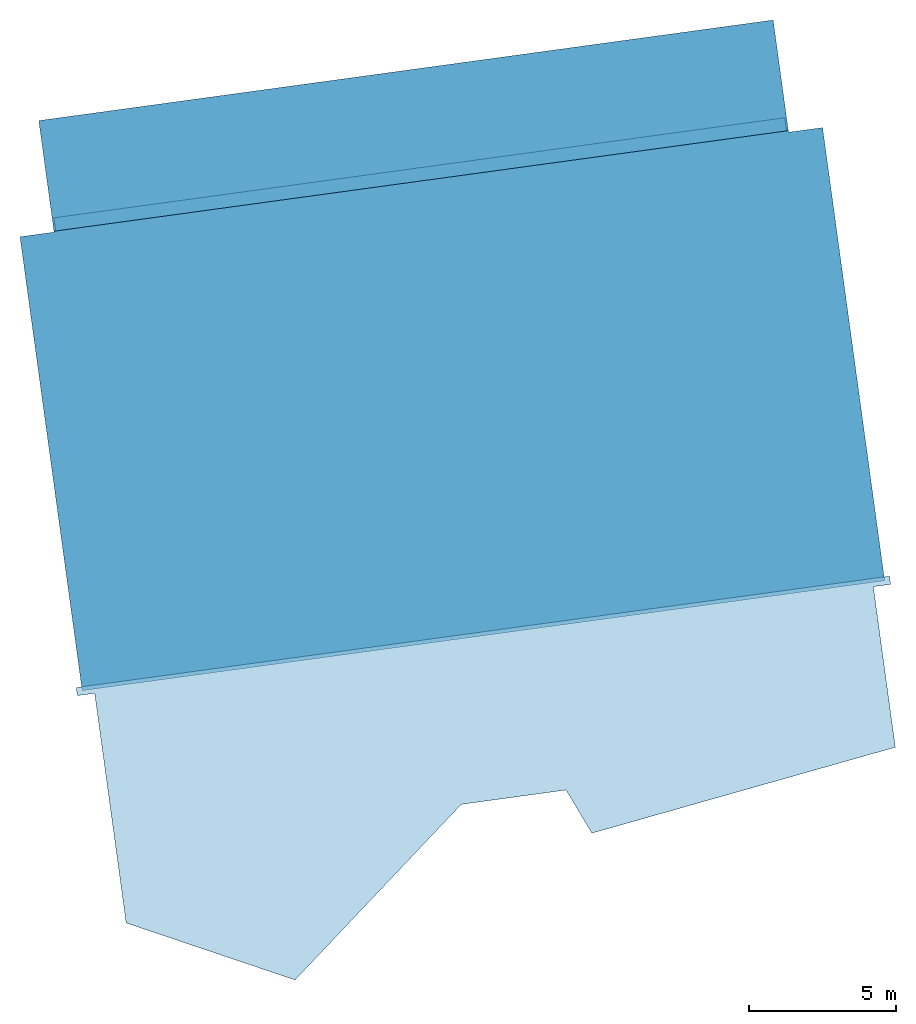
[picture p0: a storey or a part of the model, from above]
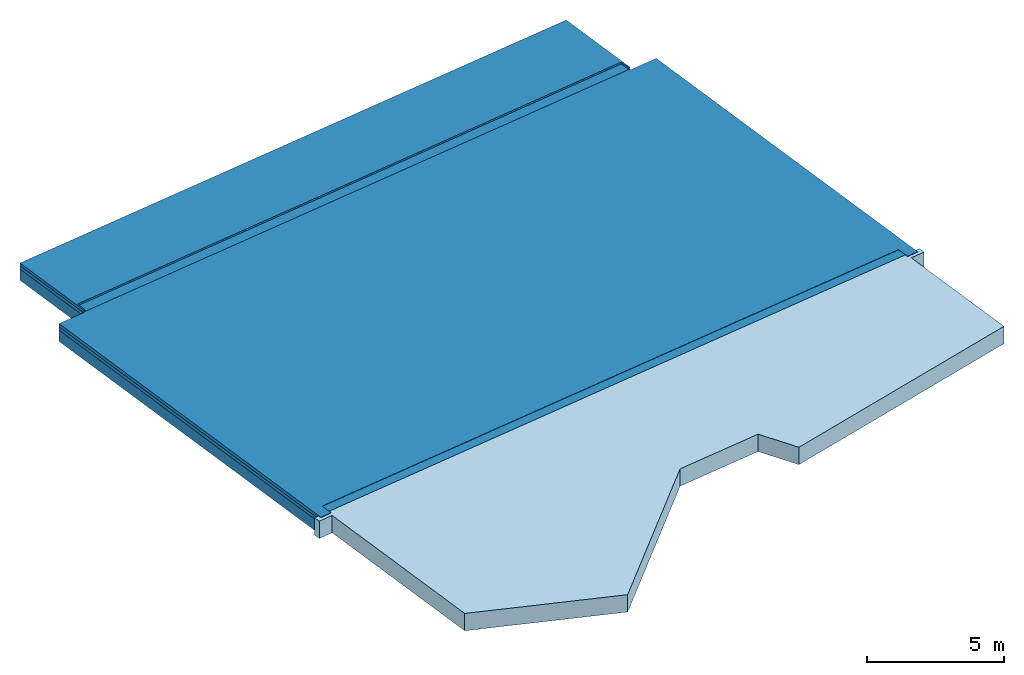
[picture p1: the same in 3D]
Properties of the parts of a building model (IFC2X3)

# File
Description: ViewDefinition [CoordinationView_V2.0], Option [Elements to export: Visible elements (on all stories)], Option [Partial Structure Display: Entire Model], Option [IFC Domain: All], Option [Structural Function: All Elements], Option [Convert Grid elements: On], Option [Convert IFC Annotations and Archicad 2D elements: Off], Option [Convert 2D symbols of Doors and Windows: Off], Option [Export geometries that Participates in Collision Detection only: Off], Option [Split complex elements: Off], Option [Material Preservation: Explode where necessary], Option [Elements in Solid Element Operations: Extruded/revolved], Option [Elements with junctions: Extruded/revolved], Option [IFC Model position: Survey Point and Project Origin], Option [Curtain Wall export mode: Single Element], Option [Railing export mode: Single Element], Option [Stair export mode: Single Element], Option [Properties To Export: All properties], Option [Space containment: Off], Option [Geometry to type objects: Off], Option [Element Properties: Off], Option [Building Material Properties: Off], Option [Element Parameters: Off], Option [Component Parameters: Off], Option [IFC Base Quantities: Off], Option [Door Window Parameters: On], Option [IFC Space boundaries: Off], Option [Archicad Zone Categories as IFC Space classification data: Off], Option [Element Classifications: On]
File name: G:\Projekte\FWS Neuwied\Sporthalle\AVA\03 Zimmer- und Holzbauarbeiten\Mit LV versenden\FWS Neuwied Sporthalle 2026-05-05.ifc
Time: 2026-05-05T07:56:59
Author: Architect
Organization: Building Designer Office
Written by: DDS_IFC v3.0
Made in: Graphisoft - Archicad - 29.0.0
Authorization: The authorising person

# IfcSite, Gelände
RefLatitude: 50, 22, 0, 0; RefLongitude: 7, 36, 0, 0; RefElevation: 0 m

# IfcBuildingStorey (5)
In: Gebäude
Name | Elevation (m)
Gelände | -3
ZG | 3
EG | 0
OG | 5.5
Dach | 9.9

# IfcBeam: Bauholz 120 x 15 (35)
In: EG
Classification: Balken / Unterzug (ARCHICAD Klassifizierung); Material: Bauholz
AC_Pset_RenovationAndPhasing - Renovation Status: Existing
Pset_BeamCommon - Reference: Bauholz 120 x 15

# IfcBeam: Bauholz 120 x 160 (46)
In: Dach
Classification: Balken / Unterzug (ARCHICAD Klassifizierung); Material: Bauholz
AC_Pset_RenovationAndPhasing - Renovation Status: Existing
Pset_BeamCommon - Reference: Bauholz 120 x 160

# IfcBeam: Bauholz 120 x 180 (46)
In: Dach
Classification: Balken / Unterzug (ARCHICAD Klassifizierung); Material: Bauholz
AC_Pset_RenovationAndPhasing - Renovation Status: Existing
Pset_BeamCommon - Reference: Bauholz 120 x 180

# IfcBeam: Bauholz 120 x 60 (105)
In: EG
Classification: Balken / Unterzug (ARCHICAD Klassifizierung); Material: Bauholz
AC_Pset_RenovationAndPhasing - Renovation Status: Existing
Pset_BeamCommon - Reference: Bauholz 120 x 60

# IfcBeam: Bauholz 140 x 240 (2)
In: ZG
Classification: Balken / Unterzug (ARCHICAD Klassifizierung); Material: Bauholz
AC_Pset_RenovationAndPhasing - Renovation Status: Existing
Pset_BeamCommon - Reference: Bauholz 140 x 240

# IfcBeam: Bauholz 180 x 120 (6)
In: EG
Classification: Balken / Unterzug (ARCHICAD Klassifizierung); Material: Bauholz
AC_Pset_RenovationAndPhasing - Renovation Status: Existing
Pset_BeamCommon - Reference: Bauholz 180 x 120

# IfcBeam: Bauholz 180 x 15 (18)
In: EG
Classification: Balken / Unterzug (ARCHICAD Klassifizierung); Material: Bauholz
AC_Pset_RenovationAndPhasing - Renovation Status: Existing
Pset_BeamCommon - Reference: Bauholz 180 x 15

# IfcBeam: Bauholz 180 x 60 (41)
In: EG
Classification: Balken / Unterzug (ARCHICAD Klassifizierung); Material: Bauholz
AC_Pset_RenovationAndPhasing - Renovation Status: Existing
Pset_BeamCommon - Reference: Bauholz 180 x 60

# IfcBeam: Bauholz 240 x 120 (23)
Classification: Balken / Unterzug (ARCHICAD Klassifizierung); Material: Bauholz
AC_Pset_RenovationAndPhasing - Renovation Status: Existing
Pset_BeamCommon - Reference: Bauholz 240 x 120
Name | In
21 x Unterzug-035 | ZG
2 x Unterzug-021 | OG

# IfcBeam: Bauholz 240 x 60 (14)
In: EG
Classification: Balken / Unterzug (ARCHICAD Klassifizierung); Material: Bauholz
AC_Pset_RenovationAndPhasing - Renovation Status: Existing
Pset_BeamCommon - Reference: Bauholz 240 x 60

# IfcBeam: Bauholz 240 x 80 (9)
In: EG
Classification: Balken / Unterzug (ARCHICAD Klassifizierung); Material: Bauholz
AC_Pset_RenovationAndPhasing - Renovation Status: Existing
Pset_BeamCommon - Reference: Bauholz 240 x 80

# IfcBeam: Holz, Bauholz 120 x 60 (50)
In: EG
Classification: Balken / Unterzug (ARCHICAD Klassifizierung); Material: Holz, Bauholz
AC_Pset_RenovationAndPhasing - Renovation Status: Existing
Pset_BeamCommon - Reference: Holz, Bauholz 120 x 60

# IfcBeam: Holz, Bauholz 180 x 60 (14)
In: EG
Classification: Balken / Unterzug (ARCHICAD Klassifizierung); Material: Holz, Bauholz
AC_Pset_RenovationAndPhasing - Renovation Status: Existing
Pset_BeamCommon - Reference: Holz, Bauholz 180 x 60
Name
2 x Unterzug-035
12 x Unterzug-021

# IfcBeam: Holz, Bauholz 240 x 120 (42)
Classification: Balken / Unterzug (ARCHICAD Klassifizierung); Material: Holz, Bauholz
Pset_BeamCommon - Reference: Holz, Bauholz 240 x 120
AC_Pset_RenovationAndPhasing - Renovation Status: Existing
Name | In
11 x Unterzug-021 | EG
7 x Unterzug-035 | ZG
10 x Unterzug-021 | ZG
14 x Unterzug-021 | OG

# IfcBeam: Holz, Bauholz 240 x 140 (6)
Classification: Balken / Unterzug (ARCHICAD Klassifizierung); Material: Holz, Bauholz
AC_Pset_RenovationAndPhasing - Renovation Status: Existing
Pset_BeamCommon - Reference: Holz, Bauholz 240 x 140
Name | In
2 x Unterzug-021 | EG
4 x Unterzug-021 | ZG

# IfcBeam: Holz, Bauholz 240 x 60 (18)
In: EG
Classification: Balken / Unterzug (ARCHICAD Klassifizierung); Material: Holz, Bauholz
Pset_BeamCommon - Reference: Holz, Bauholz 240 x 60
AC_Pset_RenovationAndPhasing - Renovation Status: Existing

# IfcBeam: Holz, Bauholz 240 x 80 (2)
In: EG
Classification: Balken / Unterzug (ARCHICAD Klassifizierung); Material: Holz, Bauholz
Pset_BeamCommon - Reference: Holz, Bauholz 240 x 80
AC_Pset_RenovationAndPhasing - Renovation Status: Existing

# IfcBeam: Holz, Bauholz-hart 100 x 200 (12)
In: ZG
Classification: Balken / Unterzug (ARCHICAD Klassifizierung); Material: Holz, Bauholz-hart
AC_Pset_RenovationAndPhasing - Renovation Status: Existing
Pset_BeamCommon - Reference: Holz, Bauholz-hart 100 x 200

# IfcBeam: Holz, Bauholz-hart 120 x 200 (8)
In: ZG
Classification: Balken / Unterzug (ARCHICAD Klassifizierung); Material: Holz, Bauholz-hart
AC_Pset_RenovationAndPhasing - Renovation Status: Existing
Pset_BeamCommon - Reference: Holz, Bauholz-hart 120 x 200

# IfcBeam: Holz, Bauholz-hart 120 x 60 (6)
In: EG
Classification: Balken / Unterzug (ARCHICAD Klassifizierung); Material: Holz, Bauholz-hart
AC_Pset_RenovationAndPhasing - Renovation Status: Existing
Pset_BeamCommon - Reference: Holz, Bauholz-hart 120 x 60

# IfcBeam: Holz, Bauholz-hart 180 x 60 (3)
In: EG
Classification: Balken / Unterzug (ARCHICAD Klassifizierung); Material: Holz, Bauholz-hart
Pset_BeamCommon - Reference: Holz, Bauholz-hart 180 x 60
AC_Pset_RenovationAndPhasing - Renovation Status: Existing
Name
Unterzug-035
2 x Unterzug-021

# IfcBeam: Holz, Bauholz-hart 240 x 120 (23)
Classification: Balken / Unterzug (ARCHICAD Klassifizierung); Material: Holz, Bauholz-hart
Pset_BeamCommon - Reference: Holz, Bauholz-hart 240 x 120
AC_Pset_RenovationAndPhasing - Renovation Status: Existing
Name | In
7 x Unterzug-021 | EG
8 x Unterzug-021 | ZG
8 x Unterzug-021 | OG

# IfcBeam: Holz, Bauholz-hart 240 x 60 (8)
In: EG
Classification: Balken / Unterzug (ARCHICAD Klassifizierung); Material: Holz, Bauholz-hart
AC_Pset_RenovationAndPhasing - Renovation Status: Existing
Pset_BeamCommon - Reference: Holz, Bauholz-hart 240 x 60

# IfcBeam: Holz, Bauholz-hart 240 x 80 (3)
In: EG
Classification: Balken / Unterzug (ARCHICAD Klassifizierung); Material: Holz, Bauholz-hart
AC_Pset_RenovationAndPhasing - Renovation Status: Existing
Pset_BeamCommon - Reference: Holz, Bauholz-hart 240 x 80

# IfcBeam: Holz, Bauholz-hart_UD 180 x 60 (2)
In: EG
Classification: Balken / Unterzug (ARCHICAD Klassifizierung); Material: Holz, Bauholz-hart_UD
AC_Pset_RenovationAndPhasing - Renovation Status: Existing
Pset_BeamCommon - Reference: Holz, Bauholz-hart_UD 180 x 60

# IfcBeam: Holz, Brettschichtholz 160 x 350 (7)
In: OG
Classification: Balken / Unterzug (ARCHICAD Klassifizierung); Material: Holz, Brettschichtholz
AC_Pset_RenovationAndPhasing - Renovation Status: Existing
Pset_BeamCommon - Reference: Holz, Brettschichtholz 160 x 350

# IfcBeam: Holz, Brettschichtholz 160 x 440 (7)
In: OG
Classification: Balken / Unterzug (ARCHICAD Klassifizierung); Material: Holz, Brettschichtholz
AC_Pset_RenovationAndPhasing - Renovation Status: Existing
Pset_BeamCommon - Reference: Holz, Brettschichtholz 160 x 440

# IfcBeam: Holz, Brettschichtholz 2000 x 160, Unterzug-031
In: OG
Classification: Balken / Unterzug (ARCHICAD Klassifizierung); Material: Holz, Brettschichtholz
AC_Pset_RenovationAndPhasing - Renovation Status: Existing
Pset_BeamCommon - Reference: Holz, Brettschichtholz 2000 x 160

# IfcBeam: Verschiedene Strukturen - 2 Segmente - 100 x 200 x 10107 (183+9924), Unterzug-034
In: ZG
Classification: Balken / Unterzug (ARCHICAD Klassifizierung)
AC_Pset_RenovationAndPhasing - Renovation Status: Existing
Pset_BeamCommon - Reference: Verschiedene Strukturen - 2 Segmente - 100 x 200 x 10107 (183+9924)

# IfcBeam: Verschiedene Strukturen - 2 Segmente - 100 x 200 x 10390 (183+10207), Unterzug-034
In: ZG
Classification: Balken / Unterzug (ARCHICAD Klassifizierung)
AC_Pset_RenovationAndPhasing - Renovation Status: Existing
Pset_BeamCommon - Reference: Verschiedene Strukturen - 2 Segmente - 100 x 200 x 10390 (183+10207)

# IfcBeam: Verschiedene Strukturen - 2 Segmente - 100 x 200 x 10497 (183+10315), Unterzug-034
In: ZG
Classification: Balken / Unterzug (ARCHICAD Klassifizierung)
Pset_BeamCommon - Reference: Verschiedene Strukturen - 2 Segmente - 100 x 200 x 10497 (183+10315)
AC_Pset_RenovationAndPhasing - Renovation Status: Existing

# IfcBeam: Verschiedene Strukturen - 2 Segmente - 100 x 200 x 10888 (183+10706), Unterzug-034
In: ZG
Classification: Balken / Unterzug (ARCHICAD Klassifizierung)
Pset_BeamCommon - Reference: Verschiedene Strukturen - 2 Segmente - 100 x 200 x 10888 (183+10706)
AC_Pset_RenovationAndPhasing - Renovation Status: Existing

# IfcBeam: Verschiedene Strukturen - 2 Segmente - 100 x 200 x 10897 (183+10714), Unterzug-034
In: ZG
Classification: Balken / Unterzug (ARCHICAD Klassifizierung)
AC_Pset_RenovationAndPhasing - Renovation Status: Existing
Pset_BeamCommon - Reference: Verschiedene Strukturen - 2 Segmente - 100 x 200 x 10897 (183+10714)

# IfcBeam: Verschiedene Strukturen - 2 Segmente - 100 x 200 x 11279 (183+11096), Unterzug-034
In: ZG
Classification: Balken / Unterzug (ARCHICAD Klassifizierung)
AC_Pset_RenovationAndPhasing - Renovation Status: Existing
Pset_BeamCommon - Reference: Verschiedene Strukturen - 2 Segmente - 100 x 200 x 11279 (183+11096)

# IfcBeam: Verschiedene Strukturen - 2 Segmente - 100 x 200 x 11416 (183+11234), Unterzug-034
In: ZG
Classification: Balken / Unterzug (ARCHICAD Klassifizierung)
Pset_BeamCommon - Reference: Verschiedene Strukturen - 2 Segmente - 100 x 200 x 11416 (183+11234)
AC_Pset_RenovationAndPhasing - Renovation Status: Existing

# IfcBeam: Verschiedene Strukturen - 2 Segmente - 100 x 200 x 1775 (1532+243) (2)
In: ZG
Classification: Balken / Unterzug (ARCHICAD Klassifizierung)
AC_Pset_RenovationAndPhasing - Renovation Status: Existing
Pset_BeamCommon - Reference: Verschiedene Strukturen - 2 Segmente - 100 x 200 x 1775 (1532+243)

# IfcBeam: Verschiedene Strukturen - 2 Segmente - 100 x 200 x 2865 (248+2617), Unterzug-034
In: ZG
Classification: Balken / Unterzug (ARCHICAD Klassifizierung)
AC_Pset_RenovationAndPhasing - Renovation Status: Existing
Pset_BeamCommon - Reference: Verschiedene Strukturen - 2 Segmente - 100 x 200 x 2865 (248+2617)

# IfcBeam: Verschiedene Strukturen - 2 Segmente - 100 x 200 x 3283 (248+3035), Unterzug-034
In: ZG
Classification: Balken / Unterzug (ARCHICAD Klassifizierung)
AC_Pset_RenovationAndPhasing - Renovation Status: Existing
Pset_BeamCommon - Reference: Verschiedene Strukturen - 2 Segmente - 100 x 200 x 3283 (248+3035)

# IfcBeam: Verschiedene Strukturen - 2 Segmente - 100 x 200 x 4243 (4076+167) (2)
In: ZG
Classification: Balken / Unterzug (ARCHICAD Klassifizierung)
AC_Pset_RenovationAndPhasing - Renovation Status: Existing
Pset_BeamCommon - Reference: Verschiedene Strukturen - 2 Segmente - 100 x 200 x 4243 (4076+167)

# IfcBeam: Verschiedene Strukturen - 2 Segmente - 100 x 200 x 4381 (4214+167) (37)
In: ZG
Classification: Balken / Unterzug (ARCHICAD Klassifizierung)
AC_Pset_RenovationAndPhasing - Renovation Status: Existing
Pset_BeamCommon - Reference: Verschiedene Strukturen - 2 Segmente - 100 x 200 x 4381 (4214+167)

# IfcBeam: Verschiedene Strukturen - 2 Segmente - 100 x 200 x 5298 (183+5116) (2)
In: ZG
Classification: Balken / Unterzug (ARCHICAD Klassifizierung)
AC_Pset_RenovationAndPhasing - Renovation Status: Existing
Pset_BeamCommon - Reference: Verschiedene Strukturen - 2 Segmente - 100 x 200 x 5298 (183+5116)

# IfcBeam: Verschiedene Strukturen - 2 Segmente - 100 x 200 x 5325 (183+5143), Unterzug-034
In: ZG
Classification: Balken / Unterzug (ARCHICAD Klassifizierung)
Pset_BeamCommon - Reference: Verschiedene Strukturen - 2 Segmente - 100 x 200 x 5325 (183+5143)
AC_Pset_RenovationAndPhasing - Renovation Status: Existing

# IfcBeam: Verschiedene Strukturen - 2 Segmente - 100 x 200 x 5412 (183+5229), Unterzug-034
In: ZG
Classification: Balken / Unterzug (ARCHICAD Klassifizierung)
AC_Pset_RenovationAndPhasing - Renovation Status: Existing
Pset_BeamCommon - Reference: Verschiedene Strukturen - 2 Segmente - 100 x 200 x 5412 (183+5229)

# IfcBeam: Verschiedene Strukturen - 2 Segmente - 100 x 200 x 5542 (183+5359), Unterzug-034
In: ZG
Classification: Balken / Unterzug (ARCHICAD Klassifizierung)
AC_Pset_RenovationAndPhasing - Renovation Status: Existing
Pset_BeamCommon - Reference: Verschiedene Strukturen - 2 Segmente - 100 x 200 x 5542 (183+5359)

# IfcBeam: Verschiedene Strukturen - 2 Segmente - 100 x 200 x 6435 (183+6253), Unterzug-034
In: ZG
Classification: Balken / Unterzug (ARCHICAD Klassifizierung)
Pset_BeamCommon - Reference: Verschiedene Strukturen - 2 Segmente - 100 x 200 x 6435 (183+6253)
AC_Pset_RenovationAndPhasing - Renovation Status: Existing

# IfcBeam: Verschiedene Strukturen - 2 Segmente - 100 x 200 x 6506 (183+6323), Unterzug-034
In: ZG
Classification: Balken / Unterzug (ARCHICAD Klassifizierung)
AC_Pset_RenovationAndPhasing - Renovation Status: Existing
Pset_BeamCommon - Reference: Verschiedene Strukturen - 2 Segmente - 100 x 200 x 6506 (183+6323)

# IfcBeam: Verschiedene Strukturen - 2 Segmente - 100 x 200 x 6565 (183+6383), Unterzug-034
In: ZG
Classification: Balken / Unterzug (ARCHICAD Klassifizierung)
Pset_BeamCommon - Reference: Verschiedene Strukturen - 2 Segmente - 100 x 200 x 6565 (183+6383)
AC_Pset_RenovationAndPhasing - Renovation Status: Existing

# IfcBeam: Verschiedene Strukturen - 2 Segmente - 100 x 200 x 6696 (183+6513), Unterzug-034
In: ZG
Classification: Balken / Unterzug (ARCHICAD Klassifizierung)
Pset_BeamCommon - Reference: Verschiedene Strukturen - 2 Segmente - 100 x 200 x 6696 (183+6513)
AC_Pset_RenovationAndPhasing - Renovation Status: Existing

# IfcBeam: Verschiedene Strukturen - 2 Segmente - 100 x 200 x 6826 (183+6643), Unterzug-034
In: ZG
Classification: Balken / Unterzug (ARCHICAD Klassifizierung)
Pset_BeamCommon - Reference: Verschiedene Strukturen - 2 Segmente - 100 x 200 x 6826 (183+6643)
AC_Pset_RenovationAndPhasing - Renovation Status: Existing

# IfcBeam: Verschiedene Strukturen - 2 Segmente - 100 x 200 x 6875 (183+6693), Unterzug-034
In: ZG
Classification: Balken / Unterzug (ARCHICAD Klassifizierung)
Pset_BeamCommon - Reference: Verschiedene Strukturen - 2 Segmente - 100 x 200 x 6875 (183+6693)
AC_Pset_RenovationAndPhasing - Renovation Status: Existing

# IfcBeam: Verschiedene Strukturen - 2 Segmente - 100 x 200 x 6969 (183+6786), Unterzug-034
In: ZG
Classification: Balken / Unterzug (ARCHICAD Klassifizierung)
AC_Pset_RenovationAndPhasing - Renovation Status: Existing
Pset_BeamCommon - Reference: Verschiedene Strukturen - 2 Segmente - 100 x 200 x 6969 (183+6786)

# IfcBeam: Verschiedene Strukturen - 2 Segmente - 100 x 200 x 7099 (183+6916), Unterzug-034
In: ZG
Classification: Balken / Unterzug (ARCHICAD Klassifizierung)
AC_Pset_RenovationAndPhasing - Renovation Status: Existing
Pset_BeamCommon - Reference: Verschiedene Strukturen - 2 Segmente - 100 x 200 x 7099 (183+6916)

# IfcBeam: Verschiedene Strukturen - 2 Segmente - 100 x 200 x 7229 (183+7046), Unterzug-034
In: ZG
Classification: Balken / Unterzug (ARCHICAD Klassifizierung)
AC_Pset_RenovationAndPhasing - Renovation Status: Existing
Pset_BeamCommon - Reference: Verschiedene Strukturen - 2 Segmente - 100 x 200 x 7229 (183+7046)

# IfcBeam: Verschiedene Strukturen - 2 Segmente - 100 x 200 x 7359 (183+7177), Unterzug-034
In: ZG
Classification: Balken / Unterzug (ARCHICAD Klassifizierung)
AC_Pset_RenovationAndPhasing - Renovation Status: Existing
Pset_BeamCommon - Reference: Verschiedene Strukturen - 2 Segmente - 100 x 200 x 7359 (183+7177)

# IfcBeam: Verschiedene Strukturen - 2 Segmente - 100 x 200 x 7489 (183+7307), Unterzug-034
In: ZG
Classification: Balken / Unterzug (ARCHICAD Klassifizierung)
AC_Pset_RenovationAndPhasing - Renovation Status: Existing
Pset_BeamCommon - Reference: Verschiedene Strukturen - 2 Segmente - 100 x 200 x 7489 (183+7307)

# IfcBeam: Verschiedene Strukturen - 2 Segmente - 100 x 200 x 7620 (183+7437), Unterzug-034
In: ZG
Classification: Balken / Unterzug (ARCHICAD Klassifizierung)
AC_Pset_RenovationAndPhasing - Renovation Status: Existing
Pset_BeamCommon - Reference: Verschiedene Strukturen - 2 Segmente - 100 x 200 x 7620 (183+7437)

# IfcBeam: Verschiedene Strukturen - 2 Segmente - 100 x 200 x 7750 (183+7567), Unterzug-034
In: ZG
Classification: Balken / Unterzug (ARCHICAD Klassifizierung)
AC_Pset_RenovationAndPhasing - Renovation Status: Existing
Pset_BeamCommon - Reference: Verschiedene Strukturen - 2 Segmente - 100 x 200 x 7750 (183+7567)

# IfcBeam: Verschiedene Strukturen - 2 Segmente - 100 x 200 x 8392 (183+8209), Unterzug-034
In: ZG
Classification: Balken / Unterzug (ARCHICAD Klassifizierung)
AC_Pset_RenovationAndPhasing - Renovation Status: Existing
Pset_BeamCommon - Reference: Verschiedene Strukturen - 2 Segmente - 100 x 200 x 8392 (183+8209)

# IfcBeam: Verschiedene Strukturen - 2 Segmente - 100 x 200 x 8869 (183+8686), Unterzug-034
In: ZG
Classification: Balken / Unterzug (ARCHICAD Klassifizierung)
AC_Pset_RenovationAndPhasing - Renovation Status: Existing
Pset_BeamCommon - Reference: Verschiedene Strukturen - 2 Segmente - 100 x 200 x 8869 (183+8686)

# IfcBeam: Verschiedene Strukturen - 2 Segmente - 100 x 200 x 9325 (183+9143), Unterzug-034
In: ZG
Classification: Balken / Unterzug (ARCHICAD Klassifizierung)
AC_Pset_RenovationAndPhasing - Renovation Status: Existing
Pset_BeamCommon - Reference: Verschiedene Strukturen - 2 Segmente - 100 x 200 x 9325 (183+9143)

# IfcBeam: Verschiedene Strukturen - 2 Segmente - 100 x 200 x 9376 (183+9193), Unterzug-034
In: ZG
Classification: Balken / Unterzug (ARCHICAD Klassifizierung)
AC_Pset_RenovationAndPhasing - Renovation Status: Existing
Pset_BeamCommon - Reference: Verschiedene Strukturen - 2 Segmente - 100 x 200 x 9376 (183+9193)

# IfcBeam: Verschiedene Strukturen - 2 Segmente - 100 x 200 x 9716 (183+9533), Unterzug-034
In: ZG
Classification: Balken / Unterzug (ARCHICAD Klassifizierung)
AC_Pset_RenovationAndPhasing - Renovation Status: Existing
Pset_BeamCommon - Reference: Verschiedene Strukturen - 2 Segmente - 100 x 200 x 9716 (183+9533)

# IfcBeam: Verschiedene Strukturen - 2 Segmente - 100 x 200 x 9883 (183+9700), Unterzug-034
In: ZG
Classification: Balken / Unterzug (ARCHICAD Klassifizierung)
Pset_BeamCommon - Reference: Verschiedene Strukturen - 2 Segmente - 100 x 200 x 9883 (183+9700)
AC_Pset_RenovationAndPhasing - Renovation Status: Existing

# IfcBeam: Verschiedene Strukturen - 2 Segmente - 120 x 200 x 11670 (183+11487), Unterzug-034
In: ZG
Classification: Balken / Unterzug (ARCHICAD Klassifizierung)
Pset_BeamCommon - Reference: Verschiedene Strukturen - 2 Segmente - 120 x 200 x 11670 (183+11487)
AC_Pset_RenovationAndPhasing - Renovation Status: Existing

# IfcBeam: Verschiedene Strukturen - 2 Segmente - 120 x 200 x 11923 (183+11741), Unterzug-034
In: ZG
Classification: Balken / Unterzug (ARCHICAD Klassifizierung)
AC_Pset_RenovationAndPhasing - Renovation Status: Existing
Pset_BeamCommon - Reference: Verschiedene Strukturen - 2 Segmente - 120 x 200 x 11923 (183+11741)

# IfcBeam: Verschiedene Strukturen - 2 Segmente - 120 x 200 x 7880 (183+7697), Unterzug-034
In: ZG
Classification: Balken / Unterzug (ARCHICAD Klassifizierung)
AC_Pset_RenovationAndPhasing - Renovation Status: Existing
Pset_BeamCommon - Reference: Verschiedene Strukturen - 2 Segmente - 120 x 200 x 7880 (183+7697)

# IfcBeam: Verschiedene Strukturen - 2 Segmente - 120 x 200 x 8252 (183+8070) (2)
In: ZG
Classification: Balken / Unterzug (ARCHICAD Klassifizierung)
Pset_BeamCommon - Reference: Verschiedene Strukturen - 2 Segmente - 120 x 200 x 8252 (183+8070)
AC_Pset_RenovationAndPhasing - Renovation Status: Existing

# IfcBeam: Verschiedene Strukturen - 2 Segmente - 120 x 200 x 8270 (183+8088), Unterzug-034
In: ZG
Classification: Balken / Unterzug (ARCHICAD Klassifizierung)
AC_Pset_RenovationAndPhasing - Renovation Status: Existing
Pset_BeamCommon - Reference: Verschiedene Strukturen - 2 Segmente - 120 x 200 x 8270 (183+8088)

# IfcBeam: Verschiedene Strukturen - 2 Segmente - 120 x 200 x 8379 (183+8197), Unterzug-034
In: ZG
Classification: Balken / Unterzug (ARCHICAD Klassifizierung)
Pset_BeamCommon - Reference: Verschiedene Strukturen - 2 Segmente - 120 x 200 x 8379 (183+8197)
AC_Pset_RenovationAndPhasing - Renovation Status: Existing

# IfcBeam: Verschiedene Strukturen - 2 Segmente - 180 x 200 x 8379 (183+8197) (2)
In: ZG
Classification: Balken / Unterzug (ARCHICAD Klassifizierung)
AC_Pset_RenovationAndPhasing - Renovation Status: Existing
Pset_BeamCommon - Reference: Verschiedene Strukturen - 2 Segmente - 180 x 200 x 8379 (183+8197)

# IfcBeam: Verschiedene Strukturen - 2 Segmente - 80 x 200 x 1055 (240+815), Unterzug-034
In: ZG
Classification: Balken / Unterzug (ARCHICAD Klassifizierung)
AC_Pset_RenovationAndPhasing - Renovation Status: Existing
Pset_BeamCommon - Reference: Verschiedene Strukturen - 2 Segmente - 80 x 200 x 1055 (240+815)

# IfcBeam: Verschiedene Strukturen - 2 Segmente - 80 x 200 x 1131 (183+949), Unterzug-034
In: ZG
Classification: Balken / Unterzug (ARCHICAD Klassifizierung)
AC_Pset_RenovationAndPhasing - Renovation Status: Existing
Pset_BeamCommon - Reference: Verschiedene Strukturen - 2 Segmente - 80 x 200 x 1131 (183+949)

# IfcBeam: Verschiedene Strukturen - 2 Segmente - 80 x 200 x 1207 (183+1024), Unterzug-034
In: ZG
Classification: Balken / Unterzug (ARCHICAD Klassifizierung)
AC_Pset_RenovationAndPhasing - Renovation Status: Existing
Pset_BeamCommon - Reference: Verschiedene Strukturen - 2 Segmente - 80 x 200 x 1207 (183+1024)

# IfcBeam: Verschiedene Strukturen - 2 Segmente - 80 x 200 x 1312 (1072+240) (2)
In: ZG
Classification: Balken / Unterzug (ARCHICAD Klassifizierung)
AC_Pset_RenovationAndPhasing - Renovation Status: Existing
Pset_BeamCommon - Reference: Verschiedene Strukturen - 2 Segmente - 80 x 200 x 1312 (1072+240)

# IfcBeam: Verschiedene Strukturen - 2 Segmente - 80 x 200 x 1347 (182+1165), Unterzug-034
In: ZG
Classification: Balken / Unterzug (ARCHICAD Klassifizierung)
AC_Pset_RenovationAndPhasing - Renovation Status: Existing
Pset_BeamCommon - Reference: Verschiedene Strukturen - 2 Segmente - 80 x 200 x 1347 (182+1165)

# IfcBeam: Verschiedene Strukturen - 2 Segmente - 80 x 200 x 1385 (1145+240) (2)
In: ZG
Classification: Balken / Unterzug (ARCHICAD Klassifizierung)
AC_Pset_RenovationAndPhasing - Renovation Status: Existing
Pset_BeamCommon - Reference: Verschiedene Strukturen - 2 Segmente - 80 x 200 x 1385 (1145+240)

# IfcBeam: Verschiedene Strukturen - 2 Segmente - 80 x 200 x 1397 (182+1215), Unterzug-034
In: ZG
Classification: Balken / Unterzug (ARCHICAD Klassifizierung)
AC_Pset_RenovationAndPhasing - Renovation Status: Existing
Pset_BeamCommon - Reference: Verschiedene Strukturen - 2 Segmente - 80 x 200 x 1397 (182+1215)

# IfcBeam: Verschiedene Strukturen - 2 Segmente - 80 x 200 x 1397 (183+1214), Unterzug-034
In: ZG
Classification: Balken / Unterzug (ARCHICAD Klassifizierung)
Pset_BeamCommon - Reference: Verschiedene Strukturen - 2 Segmente - 80 x 200 x 1397 (183+1214)
AC_Pset_RenovationAndPhasing - Renovation Status: Existing

# IfcBeam: Verschiedene Strukturen - 2 Segmente - 80 x 200 x 1447 (182+1264), Unterzug-034
In: ZG
Classification: Balken / Unterzug (ARCHICAD Klassifizierung)
AC_Pset_RenovationAndPhasing - Renovation Status: Existing
Pset_BeamCommon - Reference: Verschiedene Strukturen - 2 Segmente - 80 x 200 x 1447 (182+1264)

# IfcBeam: Verschiedene Strukturen - 2 Segmente - 80 x 200 x 1458 (1218+240) (2)
In: ZG
Classification: Balken / Unterzug (ARCHICAD Klassifizierung)
AC_Pset_RenovationAndPhasing - Renovation Status: Existing
Pset_BeamCommon - Reference: Verschiedene Strukturen - 2 Segmente - 80 x 200 x 1458 (1218+240)

# IfcBeam: Verschiedene Strukturen - 2 Segmente - 80 x 200 x 1496 (182+1314), Unterzug-034
In: ZG
Classification: Balken / Unterzug (ARCHICAD Klassifizierung)
Pset_BeamCommon - Reference: Verschiedene Strukturen - 2 Segmente - 80 x 200 x 1496 (182+1314)
AC_Pset_RenovationAndPhasing - Renovation Status: Existing

# IfcBeam: Verschiedene Strukturen - 2 Segmente - 80 x 200 x 1530 (1290+240) (2)
In: ZG
Classification: Balken / Unterzug (ARCHICAD Klassifizierung)
AC_Pset_RenovationAndPhasing - Renovation Status: Existing
Pset_BeamCommon - Reference: Verschiedene Strukturen - 2 Segmente - 80 x 200 x 1530 (1290+240)

# IfcBeam: Verschiedene Strukturen - 2 Segmente - 80 x 200 x 1546 (182+1364), Unterzug-034
In: ZG
Classification: Balken / Unterzug (ARCHICAD Klassifizierung)
AC_Pset_RenovationAndPhasing - Renovation Status: Existing
Pset_BeamCommon - Reference: Verschiedene Strukturen - 2 Segmente - 80 x 200 x 1546 (182+1364)

# IfcBeam: Verschiedene Strukturen - 2 Segmente - 80 x 200 x 1596 (240+1356), Unterzug-034
In: ZG
Classification: Balken / Unterzug (ARCHICAD Klassifizierung)
AC_Pset_RenovationAndPhasing - Renovation Status: Existing
Pset_BeamCommon - Reference: Verschiedene Strukturen - 2 Segmente - 80 x 200 x 1596 (240+1356)

# IfcBeam: Verschiedene Strukturen - 2 Segmente - 80 x 200 x 1603 (1363+240) (2)
In: ZG
Classification: Balken / Unterzug (ARCHICAD Klassifizierung)
Pset_BeamCommon - Reference: Verschiedene Strukturen - 2 Segmente - 80 x 200 x 1603 (1363+240)
AC_Pset_RenovationAndPhasing - Renovation Status: Existing

# IfcBeam: Verschiedene Strukturen - 2 Segmente - 80 x 200 x 1630 (240+1390), Unterzug-034
In: ZG
Classification: Balken / Unterzug (ARCHICAD Klassifizierung)
Pset_BeamCommon - Reference: Verschiedene Strukturen - 2 Segmente - 80 x 200 x 1630 (240+1390)
AC_Pset_RenovationAndPhasing - Renovation Status: Existing

# IfcBeam: Verschiedene Strukturen - 2 Segmente - 80 x 200 x 1645 (240+1405), Unterzug-034
In: ZG
Classification: Balken / Unterzug (ARCHICAD Klassifizierung)
AC_Pset_RenovationAndPhasing - Renovation Status: Existing
Pset_BeamCommon - Reference: Verschiedene Strukturen - 2 Segmente - 80 x 200 x 1645 (240+1405)

# IfcBeam: Verschiedene Strukturen - 2 Segmente - 80 x 200 x 1652 (1412+240) (2)
In: ZG
Classification: Balken / Unterzug (ARCHICAD Klassifizierung)
AC_Pset_RenovationAndPhasing - Renovation Status: Existing
Pset_BeamCommon - Reference: Verschiedene Strukturen - 2 Segmente - 80 x 200 x 1652 (1412+240)

# IfcBeam: Verschiedene Strukturen - 2 Segmente - 80 x 200 x 1695 (240+1455), Unterzug-034
In: ZG
Classification: Balken / Unterzug (ARCHICAD Klassifizierung)
AC_Pset_RenovationAndPhasing - Renovation Status: Existing
Pset_BeamCommon - Reference: Verschiedene Strukturen - 2 Segmente - 80 x 200 x 1695 (240+1455)

# IfcBeam: Verschiedene Strukturen - 2 Segmente - 80 x 200 x 1745 (240+1505), Unterzug-034
In: ZG
Classification: Balken / Unterzug (ARCHICAD Klassifizierung)
AC_Pset_RenovationAndPhasing - Renovation Status: Existing
Pset_BeamCommon - Reference: Verschiedene Strukturen - 2 Segmente - 80 x 200 x 1745 (240+1505)

# IfcBeam: Verschiedene Strukturen - 2 Segmente - 80 x 200 x 1794 (240+1554), Unterzug-034
In: ZG
Classification: Balken / Unterzug (ARCHICAD Klassifizierung)
Pset_BeamCommon - Reference: Verschiedene Strukturen - 2 Segmente - 80 x 200 x 1794 (240+1554)
AC_Pset_RenovationAndPhasing - Renovation Status: Existing

# IfcBeam: Verschiedene Strukturen - 2 Segmente - 80 x 200 x 1897 (183+1715), Unterzug-034
In: ZG
Classification: Balken / Unterzug (ARCHICAD Klassifizierung)
AC_Pset_RenovationAndPhasing - Renovation Status: Existing
Pset_BeamCommon - Reference: Verschiedene Strukturen - 2 Segmente - 80 x 200 x 1897 (183+1715)

# IfcBeam: Verschiedene Strukturen - 2 Segmente - 80 x 200 x 1938 (183+1756), Unterzug-034
In: ZG
Classification: Balken / Unterzug (ARCHICAD Klassifizierung)
AC_Pset_RenovationAndPhasing - Renovation Status: Existing
Pset_BeamCommon - Reference: Verschiedene Strukturen - 2 Segmente - 80 x 200 x 1938 (183+1756)

# IfcBeam: Verschiedene Strukturen - 2 Segmente - 80 x 200 x 1968 (183+1786), Unterzug-034
In: ZG
Classification: Balken / Unterzug (ARCHICAD Klassifizierung)
AC_Pset_RenovationAndPhasing - Renovation Status: Existing
Pset_BeamCommon - Reference: Verschiedene Strukturen - 2 Segmente - 80 x 200 x 1968 (183+1786)

# IfcBeam: Verschiedene Strukturen - 2 Segmente - 80 x 200 x 1979 (183+1797), Unterzug-034
In: ZG
Classification: Balken / Unterzug (ARCHICAD Klassifizierung)
Pset_BeamCommon - Reference: Verschiedene Strukturen - 2 Segmente - 80 x 200 x 1979 (183+1797)
AC_Pset_RenovationAndPhasing - Renovation Status: Existing

# IfcBeam: Verschiedene Strukturen - 2 Segmente - 80 x 200 x 1981 (183+1798), Unterzug-034
In: ZG
Classification: Balken / Unterzug (ARCHICAD Klassifizierung)
AC_Pset_RenovationAndPhasing - Renovation Status: Existing
Pset_BeamCommon - Reference: Verschiedene Strukturen - 2 Segmente - 80 x 200 x 1981 (183+1798)

# IfcBeam: Verschiedene Strukturen - 2 Segmente - 80 x 200 x 2021 (183+1838), Unterzug-034
In: ZG
Classification: Balken / Unterzug (ARCHICAD Klassifizierung)
Pset_BeamCommon - Reference: Verschiedene Strukturen - 2 Segmente - 80 x 200 x 2021 (183+1838)
AC_Pset_RenovationAndPhasing - Renovation Status: Existing

# IfcBeam: Verschiedene Strukturen - 2 Segmente - 80 x 200 x 2062 (183+1879), Unterzug-034
In: ZG
Classification: Balken / Unterzug (ARCHICAD Klassifizierung)
AC_Pset_RenovationAndPhasing - Renovation Status: Existing
Pset_BeamCommon - Reference: Verschiedene Strukturen - 2 Segmente - 80 x 200 x 2062 (183+1879)

# IfcBeam: Verschiedene Strukturen - 2 Segmente - 80 x 200 x 2103 (183+1920), Unterzug-034
In: ZG
Classification: Balken / Unterzug (ARCHICAD Klassifizierung)
AC_Pset_RenovationAndPhasing - Renovation Status: Existing
Pset_BeamCommon - Reference: Verschiedene Strukturen - 2 Segmente - 80 x 200 x 2103 (183+1920)

# IfcBeam: Verschiedene Strukturen - 2 Segmente - 80 x 200 x 2153 (183+1971), Unterzug-034
In: ZG
Classification: Balken / Unterzug (ARCHICAD Klassifizierung)
Pset_BeamCommon - Reference: Verschiedene Strukturen - 2 Segmente - 80 x 200 x 2153 (183+1971)
AC_Pset_RenovationAndPhasing - Renovation Status: Existing

# IfcBeam: Verschiedene Strukturen - 2 Segmente - 80 x 200 x 696 (529+167) (2)
In: ZG
Classification: Balken / Unterzug (ARCHICAD Klassifizierung)
AC_Pset_RenovationAndPhasing - Renovation Status: Existing
Pset_BeamCommon - Reference: Verschiedene Strukturen - 2 Segmente - 80 x 200 x 696 (529+167)

# IfcBeam: Verschiedene Strukturen - 2 Segmente - 80 x 200 x 757 (517+240) (2)
In: ZG
Classification: Balken / Unterzug (ARCHICAD Klassifizierung)
AC_Pset_RenovationAndPhasing - Renovation Status: Existing
Pset_BeamCommon - Reference: Verschiedene Strukturen - 2 Segmente - 80 x 200 x 757 (517+240)

# IfcBeam: Verschiedene Strukturen - 3 Segmente - 120 x 200 x 12890 (660+11570+660) (26)
In: OG
Classification: Balken / Unterzug (ARCHICAD Klassifizierung)
AC_Pset_RenovationAndPhasing - Renovation Status: Existing
Pset_BeamCommon - Reference: Verschiedene Strukturen - 3 Segmente - 120 x 200 x 12890 (660+11570+660)

# IfcBeam: Verschiedene Strukturen - 4 Segmente - 120 x 200 x 10040 (970+7659+1220+190) (2)
In: OG
Classification: Balken / Unterzug (ARCHICAD Klassifizierung)
Pset_BeamCommon - Reference: Verschiedene Strukturen - 4 Segmente - 120 x 200 x 10040 (970+7659+1220+190)
AC_Pset_RenovationAndPhasing - Renovation Status: Existing

# IfcBeam: Verschiedene Strukturen - 4 Segmente - 120 x 200 x 10110 (970+7659+1291+190) (2)
In: OG
Classification: Balken / Unterzug (ARCHICAD Klassifizierung)
AC_Pset_RenovationAndPhasing - Renovation Status: Existing
Pset_BeamCommon - Reference: Verschiedene Strukturen - 4 Segmente - 120 x 200 x 10110 (970+7659+1291+190)

# IfcBeam: Verschiedene Strukturen - 4 Segmente - 120 x 200 x 10184 (970+7659+1365+190) (2)
In: OG
Classification: Balken / Unterzug (ARCHICAD Klassifizierung)
AC_Pset_RenovationAndPhasing - Renovation Status: Existing
Pset_BeamCommon - Reference: Verschiedene Strukturen - 4 Segmente - 120 x 200 x 10184 (970+7659+1365+190)

# IfcBeam: Verschiedene Strukturen - 4 Segmente - 120 x 200 x 10261 (970+7659+1442+190) (2)
In: OG
Classification: Balken / Unterzug (ARCHICAD Klassifizierung)
AC_Pset_RenovationAndPhasing - Renovation Status: Existing
Pset_BeamCommon - Reference: Verschiedene Strukturen - 4 Segmente - 120 x 200 x 10261 (970+7659+1442+190)

# IfcBeam: Verschiedene Strukturen - 4 Segmente - 120 x 200 x 10342 (970+7659+1523+190) (2)
In: OG
Classification: Balken / Unterzug (ARCHICAD Klassifizierung)
AC_Pset_RenovationAndPhasing - Renovation Status: Existing
Pset_BeamCommon - Reference: Verschiedene Strukturen - 4 Segmente - 120 x 200 x 10342 (970+7659+1523+190)

# IfcBeam: Verschiedene Strukturen - 4 Segmente - 120 x 200 x 10426 (970+7659+1607+190) (2)
In: OG
Classification: Balken / Unterzug (ARCHICAD Klassifizierung)
AC_Pset_RenovationAndPhasing - Renovation Status: Existing
Pset_BeamCommon - Reference: Verschiedene Strukturen - 4 Segmente - 120 x 200 x 10426 (970+7659+1607+190)

# IfcBeam: Verschiedene Strukturen - 4 Segmente - 120 x 200 x 10509 (970+7659+1690+190) (2)
In: OG
Classification: Balken / Unterzug (ARCHICAD Klassifizierung)
AC_Pset_RenovationAndPhasing - Renovation Status: Existing
Pset_BeamCommon - Reference: Verschiedene Strukturen - 4 Segmente - 120 x 200 x 10509 (970+7659+1690+190)

# IfcBeam: Verschiedene Strukturen - 4 Segmente - 120 x 200 x 10600 (970+7659+1781+190) (2)
In: OG
Classification: Balken / Unterzug (ARCHICAD Klassifizierung)
AC_Pset_RenovationAndPhasing - Renovation Status: Existing
Pset_BeamCommon - Reference: Verschiedene Strukturen - 4 Segmente - 120 x 200 x 10600 (970+7659+1781+190)

# IfcBeam: Verschiedene Strukturen - 4 Segmente - 120 x 200 x 10694 (970+7659+1875+190) (2)
In: OG
Classification: Balken / Unterzug (ARCHICAD Klassifizierung)
Pset_BeamCommon - Reference: Verschiedene Strukturen - 4 Segmente - 120 x 200 x 10694 (970+7659+1875+190)
AC_Pset_RenovationAndPhasing - Renovation Status: Existing

# IfcBeam: Verschiedene Strukturen - 4 Segmente - 120 x 200 x 9364 (970+7659+545+190) (2)
In: OG
Classification: Balken / Unterzug (ARCHICAD Klassifizierung)
AC_Pset_RenovationAndPhasing - Renovation Status: Existing
Pset_BeamCommon - Reference: Verschiedene Strukturen - 4 Segmente - 120 x 200 x 9364 (970+7659+545+190)

# IfcBeam: Verschiedene Strukturen - 4 Segmente - 120 x 200 x 9378 (970+7659+558+190), Unterzug-031
In: OG
Classification: Balken / Unterzug (ARCHICAD Klassifizierung)
Pset_BeamCommon - Reference: Verschiedene Strukturen - 4 Segmente - 120 x 200 x 9378 (970+7659+558+190)
AC_Pset_RenovationAndPhasing - Renovation Status: Existing

# IfcBeam: Verschiedene Strukturen - 4 Segmente - 120 x 200 x 9378 (970+7659+559+190), Unterzug-031
In: OG
Classification: Balken / Unterzug (ARCHICAD Klassifizierung)
Pset_BeamCommon - Reference: Verschiedene Strukturen - 4 Segmente - 120 x 200 x 9378 (970+7659+559+190)
AC_Pset_RenovationAndPhasing - Renovation Status: Existing

# IfcBeam: Verschiedene Strukturen - 4 Segmente - 120 x 200 x 9394 (970+7659+575+190) (2)
In: OG
Classification: Balken / Unterzug (ARCHICAD Klassifizierung)
AC_Pset_RenovationAndPhasing - Renovation Status: Existing
Pset_BeamCommon - Reference: Verschiedene Strukturen - 4 Segmente - 120 x 200 x 9394 (970+7659+575+190)

# IfcBeam: Verschiedene Strukturen - 4 Segmente - 120 x 200 x 9414 (970+7659+595+190) (2)
In: OG
Classification: Balken / Unterzug (ARCHICAD Klassifizierung)
AC_Pset_RenovationAndPhasing - Renovation Status: Existing
Pset_BeamCommon - Reference: Verschiedene Strukturen - 4 Segmente - 120 x 200 x 9414 (970+7659+595+190)

# IfcBeam: Verschiedene Strukturen - 4 Segmente - 120 x 200 x 9437 (970+7659+617+190), Unterzug-031
In: OG
Classification: Balken / Unterzug (ARCHICAD Klassifizierung)
Pset_BeamCommon - Reference: Verschiedene Strukturen - 4 Segmente - 120 x 200 x 9437 (970+7659+617+190)
AC_Pset_RenovationAndPhasing - Renovation Status: Existing

# IfcBeam: Verschiedene Strukturen - 4 Segmente - 120 x 200 x 9437 (970+7659+618+190), Unterzug-031
In: OG
Classification: Balken / Unterzug (ARCHICAD Klassifizierung)
AC_Pset_RenovationAndPhasing - Renovation Status: Existing
Pset_BeamCommon - Reference: Verschiedene Strukturen - 4 Segmente - 120 x 200 x 9437 (970+7659+618+190)

# IfcBeam: Verschiedene Strukturen - 4 Segmente - 120 x 200 x 9463 (970+7659+644+190) (2)
In: OG
Classification: Balken / Unterzug (ARCHICAD Klassifizierung)
AC_Pset_RenovationAndPhasing - Renovation Status: Existing
Pset_BeamCommon - Reference: Verschiedene Strukturen - 4 Segmente - 120 x 200 x 9463 (970+7659+644+190)

# IfcBeam: Verschiedene Strukturen - 4 Segmente - 120 x 200 x 9492 (970+7659+673+190) (2)
In: OG
Classification: Balken / Unterzug (ARCHICAD Klassifizierung)
AC_Pset_RenovationAndPhasing - Renovation Status: Existing
Pset_BeamCommon - Reference: Verschiedene Strukturen - 4 Segmente - 120 x 200 x 9492 (970+7659+673+190)

# IfcBeam: Verschiedene Strukturen - 4 Segmente - 120 x 200 x 9525 (970+7659+706+190) (2)
In: OG
Classification: Balken / Unterzug (ARCHICAD Klassifizierung)
AC_Pset_RenovationAndPhasing - Renovation Status: Existing
Pset_BeamCommon - Reference: Verschiedene Strukturen - 4 Segmente - 120 x 200 x 9525 (970+7659+706+190)

# IfcBeam: Verschiedene Strukturen - 4 Segmente - 120 x 200 x 9561 (970+7659+742+190) (2)
In: OG
Classification: Balken / Unterzug (ARCHICAD Klassifizierung)
AC_Pset_RenovationAndPhasing - Renovation Status: Existing
Pset_BeamCommon - Reference: Verschiedene Strukturen - 4 Segmente - 120 x 200 x 9561 (970+7659+742+190)

# IfcBeam: Verschiedene Strukturen - 4 Segmente - 120 x 200 x 9601 (970+7659+782+190) (2)
In: OG
Classification: Balken / Unterzug (ARCHICAD Klassifizierung)
AC_Pset_RenovationAndPhasing - Renovation Status: Existing
Pset_BeamCommon - Reference: Verschiedene Strukturen - 4 Segmente - 120 x 200 x 9601 (970+7659+782+190)

# IfcBeam: Verschiedene Strukturen - 4 Segmente - 120 x 200 x 9644 (970+7659+825+190) (2)
In: OG
Classification: Balken / Unterzug (ARCHICAD Klassifizierung)
AC_Pset_RenovationAndPhasing - Renovation Status: Existing
Pset_BeamCommon - Reference: Verschiedene Strukturen - 4 Segmente - 120 x 200 x 9644 (970+7659+825+190)

# IfcBeam: Verschiedene Strukturen - 4 Segmente - 120 x 200 x 9690 (970+7659+871+190) (2)
In: OG
Classification: Balken / Unterzug (ARCHICAD Klassifizierung)
Pset_BeamCommon - Reference: Verschiedene Strukturen - 4 Segmente - 120 x 200 x 9690 (970+7659+871+190)
AC_Pset_RenovationAndPhasing - Renovation Status: Existing

# IfcBeam: Verschiedene Strukturen - 4 Segmente - 120 x 200 x 9740 (970+7659+920+190), Unterzug-031
In: OG
Classification: Balken / Unterzug (ARCHICAD Klassifizierung)
AC_Pset_RenovationAndPhasing - Renovation Status: Existing
Pset_BeamCommon - Reference: Verschiedene Strukturen - 4 Segmente - 120 x 200 x 9740 (970+7659+920+190)

# IfcBeam: Verschiedene Strukturen - 4 Segmente - 120 x 200 x 9740 (970+7659+921+190), Unterzug-031
In: OG
Classification: Balken / Unterzug (ARCHICAD Klassifizierung)
AC_Pset_RenovationAndPhasing - Renovation Status: Existing
Pset_BeamCommon - Reference: Verschiedene Strukturen - 4 Segmente - 120 x 200 x 9740 (970+7659+921+190)

# IfcBeam: Verschiedene Strukturen - 4 Segmente - 120 x 200 x 9793 (970+7659+974+190) (2)
In: OG
Classification: Balken / Unterzug (ARCHICAD Klassifizierung)
Pset_BeamCommon - Reference: Verschiedene Strukturen - 4 Segmente - 120 x 200 x 9793 (970+7659+974+190)
AC_Pset_RenovationAndPhasing - Renovation Status: Existing

# IfcBeam: Verschiedene Strukturen - 4 Segmente - 120 x 200 x 9849 (970+7659+1030+190) (2)
In: OG
Classification: Balken / Unterzug (ARCHICAD Klassifizierung)
AC_Pset_RenovationAndPhasing - Renovation Status: Existing
Pset_BeamCommon - Reference: Verschiedene Strukturen - 4 Segmente - 120 x 200 x 9849 (970+7659+1030+190)

# IfcBeam: Verschiedene Strukturen - 4 Segmente - 120 x 200 x 9909 (970+7659+1090+190) (2)
In: OG
Classification: Balken / Unterzug (ARCHICAD Klassifizierung)
Pset_BeamCommon - Reference: Verschiedene Strukturen - 4 Segmente - 120 x 200 x 9909 (970+7659+1090+190)
AC_Pset_RenovationAndPhasing - Renovation Status: Existing

# IfcBeam: Verschiedene Strukturen - 4 Segmente - 120 x 200 x 9973 (970+7659+1153+190), Unterzug-031
In: OG
Classification: Balken / Unterzug (ARCHICAD Klassifizierung)
AC_Pset_RenovationAndPhasing - Renovation Status: Existing
Pset_BeamCommon - Reference: Verschiedene Strukturen - 4 Segmente - 120 x 200 x 9973 (970+7659+1153+190)

# IfcBeam: Verschiedene Strukturen - 4 Segmente - 120 x 200 x 9973 (970+7659+1154+190), Unterzug-031
In: OG
Classification: Balken / Unterzug (ARCHICAD Klassifizierung)
Pset_BeamCommon - Reference: Verschiedene Strukturen - 4 Segmente - 120 x 200 x 9973 (970+7659+1154+190)
AC_Pset_RenovationAndPhasing - Renovation Status: Existing

# IfcBuildingElementPart (538)
Name | In | Material
2 x Boden, Kies | Gelände | Boden, Kies
2 x Boden, Schüttung | Gelände | Boden, Schüttung
2 x Dämmung, hart Mineralwolle | Gelände | Dämmung, hart Mineralwolle
246 x Holz, Bauholz-hart | ZG | Holz, Bauholz-hart
286 x Bauholz | OG | Bauholz

# IfcColumn: Bauholz 120 x 120 (5)
In: EG
Classification: Stütze (ARCHICAD Klassifizierung); Material: Bauholz
AC_Pset_RenovationAndPhasing - Renovation Status: Existing
Pset_ColumnCommon - Reference: Bauholz 120 x 120

# IfcColumn: Bauholz 120 x 180 (8)
In: EG
Classification: Stütze (ARCHICAD Klassifizierung); Material: Bauholz
AC_Pset_RenovationAndPhasing - Renovation Status: Existing
Pset_ColumnCommon - Reference: Bauholz 120 x 180

# IfcColumn: Bauholz 120 x 240 (104)
Classification: Stütze (ARCHICAD Klassifizierung); Material: Bauholz
AC_Pset_RenovationAndPhasing - Renovation Status: Existing
Pset_ColumnCommon - Reference: Bauholz 120 x 240
Name | In
43 x Stütze-018 | EG
45 x Stütze-018 | ZG
16 x Stütze-018 | OG

# IfcColumn: Bauholz 140 x 240 (2)
Classification: Stütze (ARCHICAD Klassifizierung); Material: Bauholz
AC_Pset_RenovationAndPhasing - Renovation Status: Existing
Pset_ColumnCommon - Reference: Bauholz 140 x 240
Name | In
Stütze-018 | ZG
Stütze-018 | OG

# IfcColumn: Bauholz 60 x 120 (174)
Classification: Stütze (ARCHICAD Klassifizierung); Material: Bauholz
AC_Pset_RenovationAndPhasing - Renovation Status: Existing
Pset_ColumnCommon - Reference: Bauholz 60 x 120
Name | In
157 x Stütze-018 | EG
17 x Stütze-018 | ZG

# IfcColumn: Bauholz 60 x 180 (170)
Classification: Stütze (ARCHICAD Klassifizierung); Material: Bauholz
AC_Pset_RenovationAndPhasing - Renovation Status: Existing
Pset_ColumnCommon - Reference: Bauholz 60 x 180
Name | In
154 x Stütze-018 | EG
16 x Stütze-018 | ZG

# IfcColumn: Bauholz 60 x 200 (28)
In: OG
Classification: Stütze (ARCHICAD Klassifizierung); Material: Bauholz
AC_Pset_RenovationAndPhasing - Renovation Status: Existing
Pset_ColumnCommon - Reference: Bauholz 60 x 200

# IfcColumn: Bauholz 60 x 240 (31)
In: EG
Classification: Stütze (ARCHICAD Klassifizierung); Material: Bauholz
Pset_ColumnCommon - Reference: Bauholz 60 x 240
AC_Pset_RenovationAndPhasing - Renovation Status: Existing

# IfcColumn: Bauholz 80 x 120, Stütze-018
In: EG
Classification: Stütze (ARCHICAD Klassifizierung); Material: Bauholz
Pset_ColumnCommon - Reference: Bauholz 80 x 120
AC_Pset_RenovationAndPhasing - Renovation Status: Existing

# IfcColumn: Bauholz 80 x 240 (258)
Classification: Stütze (ARCHICAD Klassifizierung); Material: Bauholz
AC_Pset_RenovationAndPhasing - Renovation Status: Existing
Pset_ColumnCommon - Reference: Bauholz 80 x 240
Name | In
108 x Stütze-018 | EG
110 x Stütze-018 | ZG
40 x Stütze-018 | OG

# IfcColumn: Holz, Bauholz 140 x 140 (2)
In: EG
Classification: Stütze (ARCHICAD Klassifizierung); Material: Holz, Bauholz
Pset_ColumnCommon - Reference: Holz, Bauholz 140 x 140
AC_Pset_RenovationAndPhasing - Renovation Status: Existing

# IfcColumn: Holz, Brettschichtholz 280 x 280 (4)
In: EG
Classification: Stütze (ARCHICAD Klassifizierung); Material: Holz, Brettschichtholz
AC_Pset_RenovationAndPhasing - Renovation Status: Existing
Pset_ColumnCommon - Reference: Holz, Brettschichtholz 280 x 280

# IfcColumn: Holz, Brettschichtholz 280 x 400 (6)
In: EG
Classification: Stütze (ARCHICAD Klassifizierung); Material: Holz, Brettschichtholz
AC_Pset_RenovationAndPhasing - Renovation Status: Existing
Pset_ColumnCommon - Reference: Holz, Brettschichtholz 280 x 400

# IfcColumn: Holz, Brettschichtholz 400 x 400 (12)
In: EG
Classification: Stütze (ARCHICAD Klassifizierung); Material: Holz, Brettschichtholz
AC_Pset_RenovationAndPhasing - Renovation Status: Existing
Pset_ColumnCommon - Reference: Holz, Brettschichtholz 400 x 400

# IfcSlab: BO | unter Bopl 790, Decke-005
In: Gelände
Type - PredefinedType: FLOOR
Classification: Decke (ARCHICAD Klassifizierung)
AC_Pset_RenovationAndPhasing - Renovation Status: Existing
Pset_SlabCommon - ThermalTransmittance: 0; IsExternal: no; LoadBearing: yes

# IfcSlab: BO | unter Bopl Geräte 770 (2)
In: Gelände
Type - PredefinedType: FLOOR
Classification: Decke (ARCHICAD Klassifizierung)
Pset_SlabCommon - ThermalTransmittance: 0; IsExternal: no; LoadBearing: yes
AC_Pset_RenovationAndPhasing - Renovation Status: Existing
Name
Decke-005 | Material: Dämmung, hart Mineralwolle 0.12 m, Boden, Schüttung 0.15 m, Boden, Kies 0.5 m
Decke-005

# IfcSlab: Bauholz, Decke-044
In: EG
Type - PredefinedType: FLOOR
Classification: Decke (ARCHICAD Klassifizierung); Material: Bauholz
Pset_SlabCommon - ThermalTransmittance: 0; IsExternal: no; LoadBearing: yes
AC_Pset_RenovationAndPhasing - Renovation Status: Existing

# IfcSlab: Beton, Stahlbeton 25 250 (3)
In: EG
Type - PredefinedType: FLOOR
Classification: Decke (ARCHICAD Klassifizierung); Material: Beton, Stahlbeton 25 0.25 m
Pset_SlabCommon - ThermalTransmittance: 0; IsExternal: no; LoadBearing: yes
AC_Pset_RenovationAndPhasing - Renovation Status: Existing

# IfcSlab: Beton, Stahlbeton 25 800 (2)
In: EG
Type - PredefinedType: FLOOR
Classification: Decke (ARCHICAD Klassifizierung); Material: Beton, Stahlbeton 25 0.8 m
AC_Pset_RenovationAndPhasing - Renovation Status: Existing
Pset_SlabCommon - ThermalTransmittance: 0; IsExternal: no; LoadBearing: yes

# IfcSlab: Holz, Bauholz (28)
In: EG
Type - PredefinedType: FLOOR
Classification: Decke (ARCHICAD Klassifizierung); Material: Holz, Bauholz
Pset_SlabCommon - ThermalTransmittance: 0; IsExternal: no; LoadBearing: yes
AC_Pset_RenovationAndPhasing - Renovation Status: Existing
Name
Decke-043
Decke-042
Decke-037
Decke-035
Decke-034
Decke-038
Decke-040
Decke-041
Decke-039
Decke-033
Decke-036
Decke-032
Decke-031
Decke-030
Decke-029
Decke-028
Decke-027
Decke-025
Decke-026
Decke-024
Decke-022
Decke-023
Decke-019
Decke-018
Decke-017
Decke-016
Decke-020
Decke-021

# IfcSlab: Holz, Brettschichtholz (8)
In: OG
Type - PredefinedType: FLOOR
Classification: Decke (ARCHICAD Klassifizierung); Material: Holz, Brettschichtholz
Pset_SlabCommon - ThermalTransmittance: 0; IsExternal: no; LoadBearing: yes
AC_Pset_RenovationAndPhasing - Renovation Status: Existing
Name
6 x Decke-018
2 x Decke-022

# IfcSlab: Holz, Brettschichtholz, Schale-002
In: ZG
Type - PredefinedType: ROOF
Classification: Dach (ARCHICAD Klassifizierung); Material: Holz, Brettschichtholz
Pset_SlabCommon - ThermalTransmittance: 0; IsExternal: yes; LoadBearing: yes
AC_Pset_RenovationAndPhasing - Renovation Status: Existing
